VERSION 5.4 ;
NAMESCASESENSITIVE ON ;
BUSBITCHARS "[]" ;
DIVIDERCHAR "/" ;
UNITS
  DATABASE MICRONS 2000 ;
END UNITS
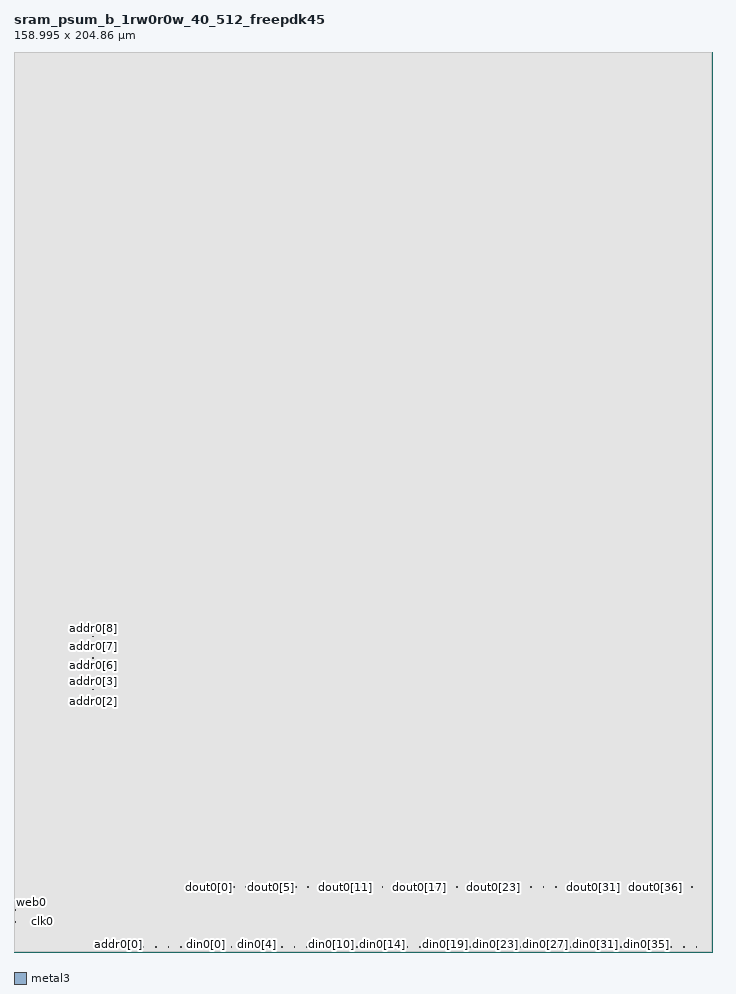
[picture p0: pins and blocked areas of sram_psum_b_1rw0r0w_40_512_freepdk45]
MACRO sram_psum_b_1rw0r0w_40_512_freepdk45
   CLASS BLOCK ;
   SIZE 158.995 BY 204.86 ;
   SYMMETRY X Y R90 ;
   PIN din0[0]
      DIRECTION INPUT ;
      PORT
         LAYER metal3 ;
         RECT 43.715 1.04 43.85 1.175 ;
      END
   END din0[0]
   PIN din0[1]
      DIRECTION INPUT ;
      PORT
         LAYER metal3 ;
         RECT 46.575 1.04 46.71 1.175 ;
      END
   END din0[1]
   PIN din0[2]
      DIRECTION INPUT ;
      PORT
         LAYER metal3 ;
         RECT 49.435 1.04 49.57 1.175 ;
      END
   END din0[2]
   PIN din0[3]
      DIRECTION INPUT ;
      PORT
         LAYER metal3 ;
         RECT 52.295 1.04 52.43 1.175 ;
      END
   END din0[3]
   PIN din0[4]
      DIRECTION INPUT ;
      PORT
         LAYER metal3 ;
         RECT 55.155 1.04 55.29 1.175 ;
      END
   END din0[4]
   PIN din0[5]
      DIRECTION INPUT ;
      PORT
         LAYER metal3 ;
         RECT 58.015 1.04 58.15 1.175 ;
      END
   END din0[5]
   PIN din0[6]
      DIRECTION INPUT ;
      PORT
         LAYER metal3 ;
         RECT 60.875 1.04 61.01 1.175 ;
      END
   END din0[6]
   PIN din0[7]
      DIRECTION INPUT ;
      PORT
         LAYER metal3 ;
         RECT 63.735 1.04 63.87 1.175 ;
      END
   END din0[7]
   PIN din0[8]
      DIRECTION INPUT ;
      PORT
         LAYER metal3 ;
         RECT 66.595 1.04 66.73 1.175 ;
      END
   END din0[8]
   PIN din0[9]
      DIRECTION INPUT ;
      PORT
         LAYER metal3 ;
         RECT 69.455 1.04 69.59 1.175 ;
      END
   END din0[9]
   PIN din0[10]
      DIRECTION INPUT ;
      PORT
         LAYER metal3 ;
         RECT 72.315 1.04 72.45 1.175 ;
      END
   END din0[10]
   PIN din0[11]
      DIRECTION INPUT ;
      PORT
         LAYER metal3 ;
         RECT 75.175 1.04 75.31 1.175 ;
      END
   END din0[11]
   PIN din0[12]
      DIRECTION INPUT ;
      PORT
         LAYER metal3 ;
         RECT 78.035 1.04 78.17 1.175 ;
      END
   END din0[12]
   PIN din0[13]
      DIRECTION INPUT ;
      PORT
         LAYER metal3 ;
         RECT 80.895 1.04 81.03 1.175 ;
      END
   END din0[13]
   PIN din0[14]
      DIRECTION INPUT ;
      PORT
         LAYER metal3 ;
         RECT 83.755 1.04 83.89 1.175 ;
      END
   END din0[14]
   PIN din0[15]
      DIRECTION INPUT ;
      PORT
         LAYER metal3 ;
         RECT 86.615 1.04 86.75 1.175 ;
      END
   END din0[15]
   PIN din0[16]
      DIRECTION INPUT ;
      PORT
         LAYER metal3 ;
         RECT 89.475 1.04 89.61 1.175 ;
      END
   END din0[16]
   PIN din0[17]
      DIRECTION INPUT ;
      PORT
         LAYER metal3 ;
         RECT 92.335 1.04 92.47 1.175 ;
      END
   END din0[17]
   PIN din0[18]
      DIRECTION INPUT ;
      PORT
         LAYER metal3 ;
         RECT 95.195 1.04 95.33 1.175 ;
      END
   END din0[18]
   PIN din0[19]
      DIRECTION INPUT ;
      PORT
         LAYER metal3 ;
         RECT 98.055 1.04 98.19 1.175 ;
      END
   END din0[19]
   PIN din0[20]
      DIRECTION INPUT ;
      PORT
         LAYER metal3 ;
         RECT 100.915 1.04 101.05 1.175 ;
      END
   END din0[20]
   PIN din0[21]
      DIRECTION INPUT ;
      PORT
         LAYER metal3 ;
         RECT 103.775 1.04 103.91 1.175 ;
      END
   END din0[21]
   PIN din0[22]
      DIRECTION INPUT ;
      PORT
         LAYER metal3 ;
         RECT 106.635 1.04 106.77 1.175 ;
      END
   END din0[22]
   PIN din0[23]
      DIRECTION INPUT ;
      PORT
         LAYER metal3 ;
         RECT 109.495 1.04 109.63 1.175 ;
      END
   END din0[23]
   PIN din0[24]
      DIRECTION INPUT ;
      PORT
         LAYER metal3 ;
         RECT 112.355 1.04 112.49 1.175 ;
      END
   END din0[24]
   PIN din0[25]
      DIRECTION INPUT ;
      PORT
         LAYER metal3 ;
         RECT 115.215 1.04 115.35 1.175 ;
      END
   END din0[25]
   PIN din0[26]
      DIRECTION INPUT ;
      PORT
         LAYER metal3 ;
         RECT 118.075 1.04 118.21 1.175 ;
      END
   END din0[26]
   PIN din0[27]
      DIRECTION INPUT ;
      PORT
         LAYER metal3 ;
         RECT 120.935 1.04 121.07 1.175 ;
      END
   END din0[27]
   PIN din0[28]
      DIRECTION INPUT ;
      PORT
         LAYER metal3 ;
         RECT 123.795 1.04 123.93 1.175 ;
      END
   END din0[28]
   PIN din0[29]
      DIRECTION INPUT ;
      PORT
         LAYER metal3 ;
         RECT 126.655 1.04 126.79 1.175 ;
      END
   END din0[29]
   PIN din0[30]
      DIRECTION INPUT ;
      PORT
         LAYER metal3 ;
         RECT 129.515 1.04 129.65 1.175 ;
      END
   END din0[30]
   PIN din0[31]
      DIRECTION INPUT ;
      PORT
         LAYER metal3 ;
         RECT 132.375 1.04 132.51 1.175 ;
      END
   END din0[31]
   PIN din0[32]
      DIRECTION INPUT ;
      PORT
         LAYER metal3 ;
         RECT 135.235 1.04 135.37 1.175 ;
      END
   END din0[32]
   PIN din0[33]
      DIRECTION INPUT ;
      PORT
         LAYER metal3 ;
         RECT 138.095 1.04 138.23 1.175 ;
      END
   END din0[33]
   PIN din0[34]
      DIRECTION INPUT ;
      PORT
         LAYER metal3 ;
         RECT 140.955 1.04 141.09 1.175 ;
      END
   END din0[34]
   PIN din0[35]
      DIRECTION INPUT ;
      PORT
         LAYER metal3 ;
         RECT 143.815 1.04 143.95 1.175 ;
      END
   END din0[35]
   PIN din0[36]
      DIRECTION INPUT ;
      PORT
         LAYER metal3 ;
         RECT 146.675 1.04 146.81 1.175 ;
      END
   END din0[36]
   PIN din0[37]
      DIRECTION INPUT ;
      PORT
         LAYER metal3 ;
         RECT 149.535 1.04 149.67 1.175 ;
      END
   END din0[37]
   PIN din0[38]
      DIRECTION INPUT ;
      PORT
         LAYER metal3 ;
         RECT 152.395 1.04 152.53 1.175 ;
      END
   END din0[38]
   PIN din0[39]
      DIRECTION INPUT ;
      PORT
         LAYER metal3 ;
         RECT 155.255 1.04 155.39 1.175 ;
      END
   END din0[39]
   PIN addr0[0]
      DIRECTION INPUT ;
      PORT
         LAYER metal3 ;
         RECT 23.695 1.04 23.83 1.175 ;
      END
   END addr0[0]
   PIN addr0[1]
      DIRECTION INPUT ;
      PORT
         LAYER metal3 ;
         RECT 26.555 1.04 26.69 1.175 ;
      END
   END addr0[1]
   PIN addr0[2]
      DIRECTION INPUT ;
      PORT
         LAYER metal3 ;
         RECT 17.975 56.915 18.11 57.05 ;
      END
   END addr0[2]
   PIN addr0[3]
      DIRECTION INPUT ;
      PORT
         LAYER metal3 ;
         RECT 17.975 59.645 18.11 59.78 ;
      END
   END addr0[3]
   PIN addr0[4]
      DIRECTION INPUT ;
      PORT
         LAYER metal3 ;
         RECT 17.975 61.855 18.11 61.99 ;
      END
   END addr0[4]
   PIN addr0[5]
      DIRECTION INPUT ;
      PORT
         LAYER metal3 ;
         RECT 17.975 64.585 18.11 64.72 ;
      END
   END addr0[5]
   PIN addr0[6]
      DIRECTION INPUT ;
      PORT
         LAYER metal3 ;
         RECT 17.975 66.795 18.11 66.93 ;
      END
   END addr0[6]
   PIN addr0[7]
      DIRECTION INPUT ;
      PORT
         LAYER metal3 ;
         RECT 17.975 69.525 18.11 69.66 ;
      END
   END addr0[7]
   PIN addr0[8]
      DIRECTION INPUT ;
      PORT
         LAYER metal3 ;
         RECT 17.975 71.735 18.11 71.87 ;
      END
   END addr0[8]
   PIN csb0
      DIRECTION INPUT ;
      PORT
         LAYER metal3 ;
         RECT 0.285 6.735 0.42 6.87 ;
      END
   END csb0
   PIN web0
      DIRECTION INPUT ;
      PORT
         LAYER metal3 ;
         RECT 0.285 9.465 0.42 9.6 ;
      END
   END web0
   PIN clk0
      DIRECTION INPUT ;
      PORT
         LAYER metal3 ;
         RECT 6.53 6.82 6.66 6.955 ;
      END
   END clk0
   PIN wmask0[0]
      DIRECTION INPUT ;
      PORT
         LAYER metal3 ;
         RECT 29.415 1.04 29.55 1.175 ;
      END
   END wmask0[0]
   PIN wmask0[1]
      DIRECTION INPUT ;
      PORT
         LAYER metal3 ;
         RECT 32.275 1.04 32.41 1.175 ;
      END
   END wmask0[1]
   PIN wmask0[2]
      DIRECTION INPUT ;
      PORT
         LAYER metal3 ;
         RECT 35.135 1.04 35.27 1.175 ;
      END
   END wmask0[2]
   PIN wmask0[3]
      DIRECTION INPUT ;
      PORT
         LAYER metal3 ;
         RECT 37.995 1.04 38.13 1.175 ;
      END
   END wmask0[3]
   PIN wmask0[4]
      DIRECTION INPUT ;
      PORT
         LAYER metal3 ;
         RECT 40.855 1.04 40.99 1.175 ;
      END
   END wmask0[4]
   PIN dout0[0]
      DIRECTION OUTPUT ;
      PORT
         LAYER metal3 ;
         RECT 44.32 14.66 44.455 14.8 ;
      END
   END dout0[0]
   PIN dout0[1]
      DIRECTION OUTPUT ;
      PORT
         LAYER metal3 ;
         RECT 47.14 14.66 47.275 14.8 ;
      END
   END dout0[1]
   PIN dout0[2]
      DIRECTION OUTPUT ;
      PORT
         LAYER metal3 ;
         RECT 49.96 14.66 50.095 14.8 ;
      END
   END dout0[2]
   PIN dout0[3]
      DIRECTION OUTPUT ;
      PORT
         LAYER metal3 ;
         RECT 52.78 14.66 52.915 14.8 ;
      END
   END dout0[3]
   PIN dout0[4]
      DIRECTION OUTPUT ;
      PORT
         LAYER metal3 ;
         RECT 55.6 14.66 55.735 14.8 ;
      END
   END dout0[4]
   PIN dout0[5]
      DIRECTION OUTPUT ;
      PORT
         LAYER metal3 ;
         RECT 58.42 14.66 58.555 14.8 ;
      END
   END dout0[5]
   PIN dout0[6]
      DIRECTION OUTPUT ;
      PORT
         LAYER metal3 ;
         RECT 61.24 14.66 61.375 14.8 ;
      END
   END dout0[6]
   PIN dout0[7]
      DIRECTION OUTPUT ;
      PORT
         LAYER metal3 ;
         RECT 64.06 14.66 64.195 14.8 ;
      END
   END dout0[7]
   PIN dout0[8]
      DIRECTION OUTPUT ;
      PORT
         LAYER metal3 ;
         RECT 66.88 14.66 67.015 14.8 ;
      END
   END dout0[8]
   PIN dout0[9]
      DIRECTION OUTPUT ;
      PORT
         LAYER metal3 ;
         RECT 69.7 14.66 69.835 14.8 ;
      END
   END dout0[9]
   PIN dout0[10]
      DIRECTION OUTPUT ;
      PORT
         LAYER metal3 ;
         RECT 72.52 14.66 72.655 14.8 ;
      END
   END dout0[10]
   PIN dout0[11]
      DIRECTION OUTPUT ;
      PORT
         LAYER metal3 ;
         RECT 75.34 14.66 75.475 14.8 ;
      END
   END dout0[11]
   PIN dout0[12]
      DIRECTION OUTPUT ;
      PORT
         LAYER metal3 ;
         RECT 78.16 14.66 78.295 14.8 ;
      END
   END dout0[12]
   PIN dout0[13]
      DIRECTION OUTPUT ;
      PORT
         LAYER metal3 ;
         RECT 80.98 14.66 81.115 14.8 ;
      END
   END dout0[13]
   PIN dout0[14]
      DIRECTION OUTPUT ;
      PORT
         LAYER metal3 ;
         RECT 83.8 14.66 83.935 14.8 ;
      END
   END dout0[14]
   PIN dout0[15]
      DIRECTION OUTPUT ;
      PORT
         LAYER metal3 ;
         RECT 86.62 14.66 86.755 14.8 ;
      END
   END dout0[15]
   PIN dout0[16]
      DIRECTION OUTPUT ;
      PORT
         LAYER metal3 ;
         RECT 89.44 14.66 89.575 14.8 ;
      END
   END dout0[16]
   PIN dout0[17]
      DIRECTION OUTPUT ;
      PORT
         LAYER metal3 ;
         RECT 92.26 14.66 92.395 14.8 ;
      END
   END dout0[17]
   PIN dout0[18]
      DIRECTION OUTPUT ;
      PORT
         LAYER metal3 ;
         RECT 95.08 14.66 95.215 14.8 ;
      END
   END dout0[18]
   PIN dout0[19]
      DIRECTION OUTPUT ;
      PORT
         LAYER metal3 ;
         RECT 97.9 14.66 98.035 14.8 ;
      END
   END dout0[19]
   PIN dout0[20]
      DIRECTION OUTPUT ;
      PORT
         LAYER metal3 ;
         RECT 100.72 14.66 100.855 14.8 ;
      END
   END dout0[20]
   PIN dout0[21]
      DIRECTION OUTPUT ;
      PORT
         LAYER metal3 ;
         RECT 103.54 14.66 103.675 14.8 ;
      END
   END dout0[21]
   PIN dout0[22]
      DIRECTION OUTPUT ;
      PORT
         LAYER metal3 ;
         RECT 106.36 14.66 106.495 14.8 ;
      END
   END dout0[22]
   PIN dout0[23]
      DIRECTION OUTPUT ;
      PORT
         LAYER metal3 ;
         RECT 109.18 14.66 109.315 14.8 ;
      END
   END dout0[23]
   PIN dout0[24]
      DIRECTION OUTPUT ;
      PORT
         LAYER metal3 ;
         RECT 112 14.66 112.135 14.8 ;
      END
   END dout0[24]
   PIN dout0[25]
      DIRECTION OUTPUT ;
      PORT
         LAYER metal3 ;
         RECT 114.82 14.66 114.955 14.8 ;
      END
   END dout0[25]
   PIN dout0[26]
      DIRECTION OUTPUT ;
      PORT
         LAYER metal3 ;
         RECT 117.64 14.66 117.775 14.8 ;
      END
   END dout0[26]
   PIN dout0[27]
      DIRECTION OUTPUT ;
      PORT
         LAYER metal3 ;
         RECT 120.46 14.66 120.595 14.8 ;
      END
   END dout0[27]
   PIN dout0[28]
      DIRECTION OUTPUT ;
      PORT
         LAYER metal3 ;
         RECT 123.28 14.66 123.415 14.8 ;
      END
   END dout0[28]
   PIN dout0[29]
      DIRECTION OUTPUT ;
      PORT
         LAYER metal3 ;
         RECT 126.1 14.66 126.235 14.8 ;
      END
   END dout0[29]
   PIN dout0[30]
      DIRECTION OUTPUT ;
      PORT
         LAYER metal3 ;
         RECT 128.92 14.66 129.055 14.8 ;
      END
   END dout0[30]
   PIN dout0[31]
      DIRECTION OUTPUT ;
      PORT
         LAYER metal3 ;
         RECT 131.74 14.66 131.875 14.8 ;
      END
   END dout0[31]
   PIN dout0[32]
      DIRECTION OUTPUT ;
      PORT
         LAYER metal3 ;
         RECT 134.56 14.66 134.695 14.8 ;
      END
   END dout0[32]
   PIN dout0[33]
      DIRECTION OUTPUT ;
      PORT
         LAYER metal3 ;
         RECT 137.38 14.66 137.515 14.8 ;
      END
   END dout0[33]
   PIN dout0[34]
      DIRECTION OUTPUT ;
      PORT
         LAYER metal3 ;
         RECT 140.2 14.66 140.335 14.8 ;
      END
   END dout0[34]
   PIN dout0[35]
      DIRECTION OUTPUT ;
      PORT
         LAYER metal3 ;
         RECT 143.02 14.66 143.155 14.8 ;
      END
   END dout0[35]
   PIN dout0[36]
      DIRECTION OUTPUT ;
      PORT
         LAYER metal3 ;
         RECT 145.84 14.66 145.975 14.8 ;
      END
   END dout0[36]
   PIN dout0[37]
      DIRECTION OUTPUT ;
      PORT
         LAYER metal3 ;
         RECT 148.66 14.66 148.795 14.8 ;
      END
   END dout0[37]
   PIN dout0[38]
      DIRECTION OUTPUT ;
      PORT
         LAYER metal3 ;
         RECT 151.48 14.66 151.615 14.8 ;
      END
   END dout0[38]
   PIN dout0[39]
      DIRECTION OUTPUT ;
      PORT
         LAYER metal3 ;
         RECT 154.3 14.66 154.435 14.8 ;
      END
   END dout0[39]
   PIN vdd
      DIRECTION INOUT ;
      USE POWER ; 
      SHAPE ABUTMENT ; 
      PORT
      END
   END vdd
   PIN gnd
      DIRECTION INOUT ;
      USE GROUND ; 
      SHAPE ABUTMENT ; 
      PORT
      END
   END gnd
   OBS
   LAYER  metal1 ;
      RECT 0.14 0.14 158.855 204.72 ;
   LAYER  metal2 ;
      RECT 0.14 0.14 158.855 204.72 ;
   END
END    sram_psum_b_1rw0r0w_40_512_freepdk45
END    LIBRARY
